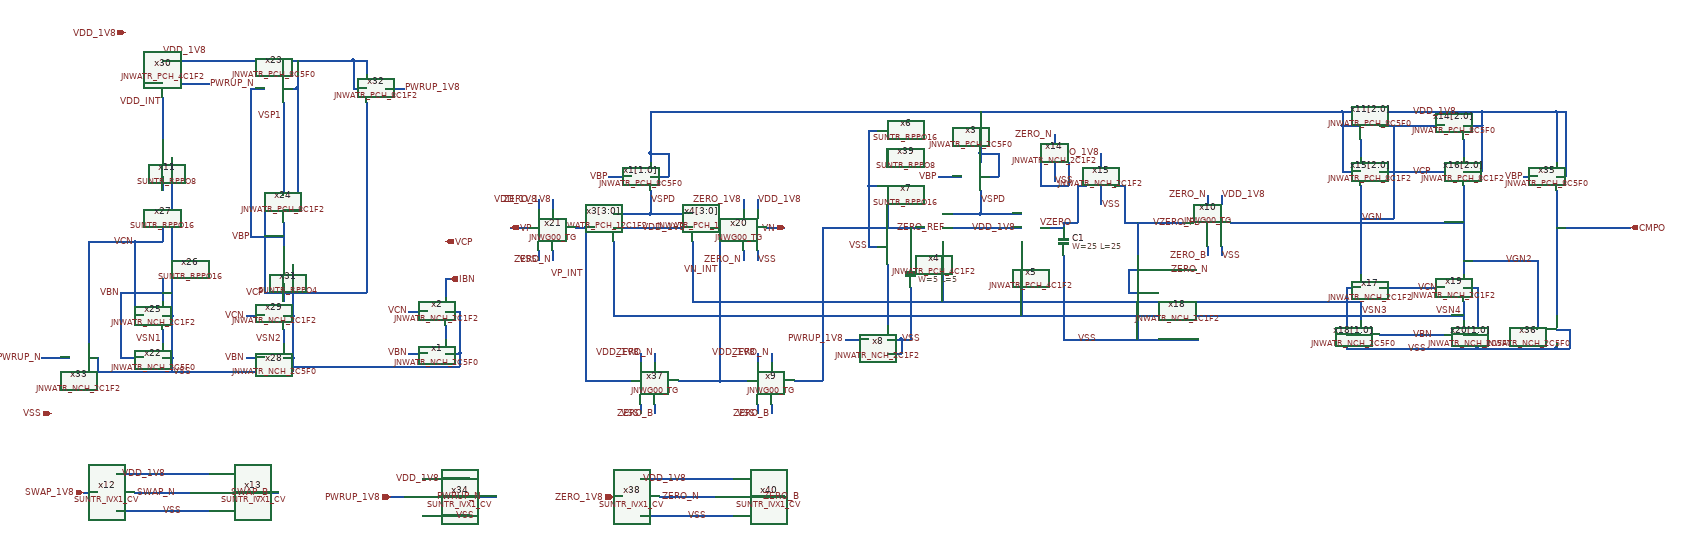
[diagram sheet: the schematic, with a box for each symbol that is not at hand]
v {xschem version=3.4.5 file_version=1.2
}
G {}
K {}
V {}
S {}
E {}
N 360 -610 460 -610 {
lab=VDD_1V8}
N 360 -530 460 -530 {
lab=VSS}
N 400 -570 420 -570 {
lab=SWAP_N}
N 290 -570 320 -570 {
lab=SWAP_1V8}
N 460 -530 560 -530 {
lab=VSS}
N 460 -610 550 -610 {
lab=VDD_1V8}
N 420 -570 520 -570 {
lab=SWAP_N}
N 600 -570 710 -570 {
lab=SWAP_B}
N 3000 -1360 3040 -1360 {
lab=VDD_1V8}
N 3000 -1390 3000 -1360 {
lab=VDD_1V8}
N 3000 -1390 3040 -1390 {
lab=VDD_1V8}
N 3040 -1390 3260 -1390 {
lab=VDD_1V8}
N 3260 -1360 3300 -1360 {
lab=VDD_1V8}
N 3300 -1390 3300 -1360 {
lab=VDD_1V8}
N 3260 -1390 3300 -1390 {
lab=VDD_1V8}
N 3260 -1330 3260 -1290 {
lab=#net1}
N 3040 -1330 3040 -1290 {
lab=#net2}
N 3000 -1260 3040 -1260 {
lab=VDD_1V8}
N 3000 -1360 3000 -1260 {
lab=VDD_1V8}
N 3260 -1260 3300 -1260 {
lab=VDD_1V8}
N 3300 -1360 3300 -1260 {
lab=VDD_1V8}
N 3040 -980 3040 -940 {
lab=VSN3}
N 3010 -1010 3040 -1010 {
lab=VSS}
N 3010 -1010 3010 -880 {
lab=VSS}
N 3010 -880 3040 -880 {
lab=VSS}
N 3010 -910 3040 -910 {
lab=VSS}
N 3260 -980 3260 -940 {
lab=VSN4}
N 3260 -1010 3290 -1010 {
lab=VSS}
N 3290 -1010 3290 -880 {
lab=VSS}
N 3260 -880 3290 -880 {
lab=VSS}
N 3260 -910 3290 -910 {
lab=VSS}
N 3040 -1230 3040 -1040 {
lab=VGN}
N 3040 -880 3260 -880 {
lab=VSS}
N 3080 -910 3120 -910 {
lab=VBN}
N 3080 -1010 3220 -1010 {
lab=VCN}
N 3080 -1260 3220 -1260 {
lab=VCP}
N 3080 -1360 3220 -1360 {
lab=VGN}
N 460 -920 460 -890 {
lab=VSN1}
N 460 -860 480 -860 {
lab=VSS}
N 480 -860 480 -830 {
lab=VSS}
N 460 -830 480 -830 {
lab=VSS}
N 480 -950 480 -860 {
lab=VSS}
N 460 -950 480 -950 {
lab=VSS}
N 460 -1030 460 -980 {
lab=VBN}
N 370 -860 420 -860 {
lab=VBN}
N 370 -1000 370 -860 {
lab=VBN}
N 370 -1000 460 -1000 {
lab=VBN}
N 400 -950 420 -950 {
lab=VCN}
N 400 -1110 400 -950 {
lab=VCN}
N 400 -1110 460 -1110 {
lab=VCN}
N 480 -1070 480 -950 {
lab=VSS}
N 480 -1180 480 -1070 {
lab=VSS}
N 460 -1140 460 -1110 {
lab=VCN}
N 420 -1450 460 -1450 {
lab=VDD_1V8}
N 420 -1480 420 -1450 {
lab=VDD_1V8}
N 420 -1480 460 -1480 {
lab=VDD_1V8}
N 460 -1520 460 -1480 {
lab=VDD_1V8}
N 500 -1450 560 -1450 {
lab=PWRUP_N}
N 720 -920 720 -890 {
lab=VSN2}
N 720 -950 740 -950 {
lab=VSS}
N 740 -950 740 -860 {
lab=VSS}
N 720 -860 740 -860 {
lab=VSS}
N 720 -830 740 -830 {
lab=VSS}
N 740 -860 740 -830 {
lab=VSS}
N 640 -950 680 -950 {
lab=VCN}
N 640 -860 680 -860 {
lab=VBN}
N 740 -1060 740 -950 {
lab=VSS}
N 720 -1020 720 -980 {
lab=VCP}
N 720 -1150 720 -1100 {
lab=VBP}
N 720 -1180 750 -1180 {
lab=VDD_1V8}
N 750 -1280 750 -1180 {
lab=VDD_1V8}
N 720 -1440 750 -1440 {
lab=VDD_1V8}
N 750 -1470 750 -1440 {
lab=VDD_1V8}
N 720 -1410 720 -1370 {
lab=VSP1}
N 680 -1180 680 -1000 {
lab=VCP}
N 680 -1000 720 -1000 {
lab=VCP}
N 650 -1120 720 -1120 {
lab=VBP}
N 650 -1280 650 -1120 {
lab=VBP}
N 650 -1440 680 -1440 {
lab=VBP}
N 460 -1500 720 -1500 {
lab=VDD_1V8}
N 720 -1500 720 -1470 {
lab=VDD_1V8}
N 900 -1260 900 -1000 {
lab=VCP}
N 720 -1000 900 -1000 {
lab=VCP}
N 870 -1440 900 -1440 {
lab=VDD_1V8}
N 870 -1500 870 -1440 {
lab=VDD_1V8}
N 870 -1500 900 -1500 {
lab=VDD_1V8}
N 900 -1500 900 -1470 {
lab=VDD_1V8}
N 720 -1500 870 -1500 {
lab=VDD_1V8}
N 940 -1440 980 -1440 {
lab=PWRUP_1V8}
N 300 -830 460 -830 {
lab=VSS}
N 300 -860 320 -860 {
lab=VSS}
N 320 -860 320 -830 {
lab=VSS}
N 300 -1110 300 -890 {
lab=VCN}
N 300 -1110 400 -1110 {
lab=VCN}
N 200 -860 260 -860 {
lab=PWRUP_N}
N 480 -830 720 -830 {
lab=VSS}
N 1020 -600 1120 -600 {
lab=VDD_1V8}
N 1020 -520 1120 -520 {
lab=VSS}
N 1060 -560 1080 -560 {
lab=PWRUP_N}
N 950 -560 980 -560 {
lab=PWRUP_1V8}
N 1080 -560 1180 -560 {
lab=PWRUP_N}
N 3120 -910 3220 -910 {
lab=VBN}
N 750 -1500 750 -1470 {
lab=VDD_1V8}
N 550 -610 560 -610 {
lab=VDD_1V8}
N 750 -1440 750 -1280 {
lab=VDD_1V8}
N 720 -1370 720 -1210 {
lab=VSP1}
N 900 -1410 900 -1260 {
lab=VCP}
N 460 -1250 460 -1220 {
lab=#net3}
N 480 -1290 480 -1180 {
lab=VSS}
N 650 -1440 650 -1280 {
lab=VBP}
N 460 -1340 460 -1330 {
lab=VDD_INT}
N 460 -1420 460 -1400 {
lab=VDD_INT}
N 3260 -1100 3260 -1040 {
lab=VGN2}
N 3260 -1230 3260 -1180 {
lab=VGN2}
N 3460 -1390 3460 -1280 {
lab=VDD_1V8}
N 3300 -1390 3460 -1390 {
lab=VDD_1V8}
N 3460 -1250 3480 -1250 {
lab=VDD_1V8}
N 3480 -1390 3480 -1250 {
lab=VDD_1V8}
N 3460 -1390 3480 -1390 {
lab=VDD_1V8}
N 3460 -890 3460 -880 {
lab=VSS}
N 3290 -880 3460 -880 {
lab=VSS}
N 3460 -920 3490 -920 {
lab=VSS}
N 3490 -920 3490 -880 {
lab=VSS}
N 3460 -880 3490 -880 {
lab=VSS}
N 3460 -980 3460 -950 {
lab=CMPO}
N 3460 -1220 3460 -980 {
lab=CMPO}
N 3460 -1140 3620 -1140 {
lab=CMPO}
N 3390 -1250 3420 -1250 {
lab=VBP}
N 3420 -1070 3420 -920 {
lab=VGN2}
N 3260 -1070 3420 -1070 {
lab=VGN2}
N 3260 -1180 3260 -1100 {
lab=VGN2}
N 1510 -1250 1550 -1250 {
lab=VDD_1V8}
N 1550 -1300 1550 -1250 {
lab=VDD_1V8}
N 1510 -1300 1550 -1300 {
lab=VDD_1V8}
N 1510 -1300 1510 -1280 {
lab=VDD_1V8}
N 1510 -1220 1510 -1170 {
lab=VSPD}
N 1430 -1170 1510 -1170 {
lab=VSPD}
N 1510 -1170 1600 -1170 {
lab=VSPD}
N 1430 -1140 1600 -1140 {
lab=VDD_1V8}
N 1550 -1390 3000 -1390 {
lab=VDD_1V8}
N 1600 -1110 1600 -980 {
lab=VSN3}
N 1600 -980 3040 -980 {
lab=VSN3}
N 1430 -1110 1430 -950 {
lab=VSN4}
N 1430 -950 3260 -950 {
lab=VSN4}
N 1420 -1250 1470 -1250 {
lab=VBP}
N 460 -1400 460 -1340 {
lab=VDD_INT}
N 1510 -1390 1510 -1300 {
lab=VDD_1V8}
N 1510 -1390 1550 -1390 {
lab=VDD_1V8}
N 3110 -1360 3110 -1160 {
lab=VGN}
N 3040 -1160 3110 -1160 {
lab=VGN}
N 990 -960 1030 -960 {
lab=VCN}
N 990 -870 1030 -870 {
lab=VBN}
N 740 -840 1070 -840 {
lab=VSS}
N 1070 -1030 1080 -1030 {
lab=IBN}
N 1070 -1030 1070 -990 {
lab=IBN}
N 1070 -930 1070 -900 {
lab=#net4}
N 1070 -960 1100 -960 {
lab=VSS}
N 1100 -960 1100 -870 {
lab=VSS}
N 1070 -870 1100 -870 {
lab=VSS}
N 1070 -840 1100 -840 {
lab=VSS}
N 1100 -870 1100 -840 {
lab=VSS}
N 1980 -1100 2000 -1100 {
lab=VSS}
N 1980 -1230 1980 -1100 {
lab=VSS}
N 2020 -1060 2020 -930 {
lab=#net5}
N 2020 -900 2050 -900 {
lab=VSS}
N 2050 -900 2050 -870 {
lab=VSS}
N 2020 -870 2050 -870 {
lab=VSS}
N 1930 -900 1980 -900 {
lab=PWRUP_1V8}
N 2020 -1190 2020 -1140 {
lab=ZERO_REF}
N 2020 -1140 2100 -1140 {
lab=ZERO_REF}
N 2400 -1080 2400 -900 {
lab=VSS}
N 2070 -1140 2070 -1070 {
lab=ZERO_REF}
N 2070 -1010 2070 -900 {
lab=VSS}
N 2050 -900 2070 -900 {
lab=VSS}
N 2350 -1140 2400 -1140 {
lab=VZERO}
N 2400 -1150 2400 -1140 {
lab=VZERO}
N 2400 -900 2500 -900 {
lab=VSS}
N 2530 -1150 2660 -1150 {
lab=VZERO_FB}
N 2500 -900 2690 -900 {
lab=VSS}
N 2560 -1150 2560 -1080 {
lab=VZERO_FB}
N 2560 -1020 2560 -900 {
lab=VSS}
N 1640 -1140 1660 -1140 {
lab=VN_INT}
N 1740 -1200 1740 -1180 {
lab=VDD_1V8}
N 1710 -1200 1710 -1180 {
lab=ZERO_1V8}
N 1710 -1090 1710 -1070 {
lab=ZERO_N}
N 1740 -1090 1740 -1070 {
lab=VSS}
N 1350 -1140 1370 -1140 {
lab=VP_INT}
N 1270 -1200 1270 -1180 {
lab=VDD_1V8}
N 1300 -1200 1300 -1180 {
lab=ZERO_1V8}
N 1300 -1090 1300 -1070 {
lab=ZERO_N}
N 1270 -1090 1270 -1070 {
lab=VSS}
N 1370 -1140 1390 -1140 {
lab=VP_INT}
N 1490 -870 1490 -850 {
lab=VDD_1V8}
N 1520 -870 1520 -850 {
lab=ZERO_N}
N 1520 -760 1520 -740 {
lab=ZERO_B}
N 1490 -760 1490 -740 {
lab=VSS}
N 1570 -810 1660 -810 {
lab=VN_INT}
N 1660 -1140 1660 -810 {
lab=VN_INT}
N 1370 -810 1460 -810 {
lab=VP_INT}
N 1370 -1140 1370 -810 {
lab=VP_INT}
N 1210 -1140 1250 -1140 {
lab=VP}
N 1760 -1140 1800 -1140 {
lab=VN}
N 1490 -600 1590 -600 {
lab=VDD_1V8}
N 1490 -520 1590 -520 {
lab=VSS}
N 1530 -560 1550 -560 {
lab=ZERO_N}
N 1550 -560 1650 -560 {
lab=ZERO_N}
N 1430 -560 1450 -560 {
lab=ZERO_1V8}
N 1460 -810 1470 -810 {
lab=VP_INT}
N 2220 -1250 2260 -1250 {
lab=VDD_1V8}
N 2260 -1300 2260 -1250 {
lab=VDD_1V8}
N 2220 -1300 2260 -1300 {
lab=VDD_1V8}
N 2220 -1300 2220 -1280 {
lab=VDD_1V8}
N 2220 -1220 2220 -1170 {
lab=VSPD}
N 2140 -1170 2220 -1170 {
lab=VSPD}
N 2220 -1170 2310 -1170 {
lab=VSPD}
N 2140 -1140 2310 -1140 {
lab=VDD_1V8}
N 2130 -1250 2180 -1250 {
lab=VBP}
N 2220 -1390 2220 -1300 {
lab=VDD_1V8}
N 1980 -1350 2000 -1350 {
lab=VSS}
N 1980 -1350 1980 -1230 {
lab=VSS}
N 2020 -1310 2020 -1270 {
lab=#net6}
N 1980 -1230 2000 -1230 {
lab=VSS}
N 2600 -1050 2630 -1050 {
lab=ZERO_N}
N 1590 -600 1680 -600 {
lab=VDD_1V8}
N 1590 -520 1690 -520 {
lab=VSS}
N 1730 -560 1800 -560 {
lab=ZERO_B}
N 2740 -1210 2740 -1190 {
lab=VDD_1V8}
N 2710 -1210 2710 -1190 {
lab=ZERO_N}
N 2710 -1100 2710 -1080 {
lab=ZERO_B}
N 2740 -1100 2740 -1080 {
lab=VSS}
N 2540 -1050 2560 -1050 {
lab=VSS}
N 2540 -1050 2540 -1000 {
lab=VSS}
N 2540 -1000 2560 -1000 {
lab=VSS}
N 2400 -1150 2430 -1150 {
lab=VZERO}
N 1680 -600 1690 -600 {
lab=VDD_1V8}
N 1740 -870 1740 -850 {
lab=VDD_1V8}
N 1770 -870 1770 -850 {
lab=ZERO_N}
N 1770 -760 1770 -740 {
lab=ZERO_B}
N 1740 -760 1740 -740 {
lab=VSS}
N 1660 -810 1720 -810 {
lab=VN_INT}
N 1880 -1140 2020 -1140 {
lab=ZERO_REF}
N 1880 -1140 1880 -810 {
lab=ZERO_REF}
N 1820 -810 1880 -810 {
lab=ZERO_REF}
N 2430 -1230 2450 -1230 {
lab=VZERO}
N 2430 -1230 2430 -1150 {
lab=VZERO}
N 2510 -1230 2530 -1230 {
lab=VZERO_FB}
N 2530 -1230 2530 -1150 {
lab=VZERO_FB}
N 2480 -1230 2480 -1190 {
lab=VSS}
N 2480 -1300 2480 -1270 {
lab=ZERO_1V8}
N 2380 -1280 2380 -1240 {
lab=VSS}
N 2410 -1280 2410 -1230 {
lab=#net7}
N 2350 -1280 2350 -1230 {
lab=#net7}
N 2350 -1230 2410 -1230 {
lab=#net7}
N 2380 -1340 2380 -1320 {
lab=ZERO_N}
N 2760 -1150 3260 -1150 {
lab=VGN2}
N 2140 -1110 2140 -980 {
lab=VSN3}
N 2310 -1110 2310 -950 {
lab=VSN4}
C {devices/ipin.sym} 290 -570 0 0 {name=p10 lab=SWAP_1V8}
C {SUN_TR_SKY130NM/SUNTR_IVX1_CV.sym} 320 -570 0 0 {name=x12 }
C {SUN_TR_SKY130NM/SUNTR_IVX1_CV.sym} 520 -570 0 0 {name=x13 }
C {devices/lab_wire.sym} 470 -610 0 0 {name=p11 sig_type=std_logic lab=VDD_1V8}
C {devices/lab_wire.sym} 490 -570 0 0 {name=p12 sig_type=std_logic lab=SWAP_N}
C {devices/lab_wire.sym} 690 -570 0 0 {name=p13 sig_type=std_logic lab=SWAP_B}
C {devices/lab_wire.sym} 460 -530 0 1 {name=p14 sig_type=std_logic lab=VSS}
C {devices/ipin.sym} 1800 -1140 2 0 {name=p25 lab=VN}
C {devices/ipin.sym} 1210 -1140 2 1 {name=p26 lab=VP}
C {JNW_ATR_SKY130NM/JNWATR_PCH_8C5F0.sym} 3080 -1360 0 1 {name=x11[2:0]}
C {JNW_ATR_SKY130NM/JNWATR_PCH_8C5F0.sym} 3220 -1360 0 0 {name=x14[2:0]}
C {JNW_ATR_SKY130NM/JNWATR_PCH_8C1F2.sym} 3080 -1260 0 1 {name=x15[2:0]}
C {JNW_ATR_SKY130NM/JNWATR_PCH_8C1F2.sym} 3220 -1260 0 0 {name=x16[2:0]}
C {JNW_ATR_SKY130NM/JNWATR_NCH_2C1F2.sym} 3080 -1010 0 1 {name=x17 }
C {JNW_ATR_SKY130NM/JNWATR_NCH_2C5F0.sym} 3080 -910 0 1 {name=x18[1:0]}
C {JNW_ATR_SKY130NM/JNWATR_NCH_2C1F2.sym} 3220 -1010 0 0 {name=x19 }
C {JNW_ATR_SKY130NM/JNWATR_NCH_2C5F0.sym} 3220 -910 0 0 {name=x20[1:0]}
C {devices/lab_wire.sym} 3140 -880 0 1 {name=p9 sig_type=std_logic lab=VSS}
C {devices/lab_wire.sym} 3150 -1390 0 1 {name=p27 sig_type=std_logic lab=VDD_1V8}
C {devices/lab_wire.sym} 3160 -1010 0 1 {name=p28 sig_type=std_logic lab=VCN}
C {devices/lab_wire.sym} 3150 -1260 0 1 {name=p29 sig_type=std_logic lab=VCP}
C {JNW_ATR_SKY130NM/JNWATR_NCH_2C5F0.sym} 420 -860 0 0 {name=x22 }
C {JNW_ATR_SKY130NM/JNWATR_PCH_8C5F0.sym} 680 -1440 0 0 {name=x23 }
C {JNW_ATR_SKY130NM/JNWATR_PCH_8C1F2.sym} 680 -1180 0 0 {name=x24 }
C {JNW_ATR_SKY130NM/JNWATR_NCH_2C1F2.sym} 420 -950 0 0 {name=x25 }
C {SUN_TR_SKY130NM/SUNTR_RPPO16.sym} 460 -1030 3 0 {name=x26 }
C {SUN_TR_SKY130NM/SUNTR_RPPO16.sym} 460 -1140 3 0 {name=x27 }
C {devices/lab_wire.sym} 460 -1520 0 1 {name=p33 sig_type=std_logic lab=VDD_1V8}
C {devices/lab_wire.sym} 480 -830 0 1 {name=p34 sig_type=std_logic lab=VSS}
C {JNW_ATR_SKY130NM/JNWATR_NCH_2C5F0.sym} 680 -860 0 0 {name=x28 }
C {JNW_ATR_SKY130NM/JNWATR_NCH_2C1F2.sym} 680 -950 0 0 {name=x29 }
C {JNW_ATR_SKY130NM/JNWATR_PCH_4C1F2.sym} 500 -1450 0 1 {name=x30 }
C {devices/lab_wire.sym} 560 -1450 0 1 {name=p35 sig_type=std_logic lab=PWRUP_N}
C {devices/lab_wire.sym} 370 -1000 0 0 {name=p36 sig_type=std_logic lab=VBN}
C {devices/lab_wire.sym} 400 -1110 0 0 {name=p37 sig_type=std_logic lab=VCN}
C {devices/lab_wire.sym} 640 -950 0 0 {name=p38 sig_type=std_logic lab=VCN}
C {devices/lab_wire.sym} 640 -860 0 0 {name=p39 sig_type=std_logic lab=VBN}
C {SUN_TR_SKY130NM/SUNTR_RPPO4.sym} 720 -1020 3 0 {name=x31 }
C {devices/lab_wire.sym} 680 -1000 0 0 {name=p40 sig_type=std_logic lab=VCP}
C {devices/lab_wire.sym} 650 -1120 0 0 {name=p41 sig_type=std_logic lab=VBP}
C {JNW_ATR_SKY130NM/JNWATR_PCH_8C1F2.sym} 940 -1440 0 1 {name=x32 }
C {devices/lab_wire.sym} 980 -1440 0 1 {name=p42 sig_type=std_logic lab=PWRUP_1V8}
C {JNW_ATR_SKY130NM/JNWATR_NCH_2C1F2.sym} 260 -860 0 0 {name=x33 }
C {devices/lab_wire.sym} 200 -860 0 0 {name=p43 sig_type=std_logic lab=PWRUP_N}
C {devices/ipin.sym} 220 -740 0 0 {name=p45 lab=VSS}
C {devices/ipin.sym} 1430 -560 0 0 {name=p46 lab=ZERO_1V8}
C {devices/ipin.sym} 950 -560 0 0 {name=p47 lab=PWRUP_1V8}
C {SUN_TR_SKY130NM/SUNTR_IVX1_CV.sym} 980 -560 0 0 {name=x34 }
C {devices/lab_wire.sym} 1060 -600 0 0 {name=p48 sig_type=std_logic lab=VDD_1V8}
C {devices/lab_wire.sym} 1150 -560 0 0 {name=p49 sig_type=std_logic lab=PWRUP_N}
C {devices/lab_wire.sym} 1090 -520 0 1 {name=p51 sig_type=std_logic lab=VSS}
C {devices/opin.sym} 3620 -1140 0 0 {name=p50 lab=CMPO
}
C {devices/ipin.sym} 380 -1560 0 0 {name=p44 lab=VDD_1V8}
C {devices/lab_wire.sym} 460 -900 0 0 {name=p53 sig_type=std_logic lab=VSN1}
C {devices/lab_wire.sym} 720 -900 0 0 {name=p54 sig_type=std_logic lab=VSN2}
C {devices/lab_wire.sym} 720 -1380 0 0 {name=p55 sig_type=std_logic lab=VSP1}
C {devices/lab_wire.sym} 460 -1410 0 0 {name=p57 sig_type=std_logic lab=VDD_INT}
C {devices/lab_wire.sym} 3040 -1160 0 1 {name=p60 sig_type=std_logic lab=VGN}
C {devices/lab_wire.sym} 3040 -960 0 1 {name=p61 sig_type=std_logic lab=VSN3}
C {devices/lab_wire.sym} 3260 -960 0 0 {name=p62 sig_type=std_logic lab=VSN4}
C {SUN_TR_SKY130NM/SUNTR_RPPO8.sym} 460 -1250 3 0 {name=x11 }
C {JNW_ATR_SKY130NM/JNWATR_PCH_8C5F0.sym} 3420 -1250 0 0 {name=x35 }
C {JNW_ATR_SKY130NM/JNWATR_NCH_2C5F0.sym} 3420 -920 0 0 {name=x36 }
C {devices/lab_wire.sym} 3350 -1070 0 1 {name=p64 sig_type=std_logic lab=VGN2}
C {devices/lab_wire.sym} 3390 -1250 0 0 {name=p63 sig_type=std_logic lab=VBP}
C {JNW_ATR_SKY130NM/JNWATR_PCH_12C1F2.sym} 1390 -1140 0 0 {name=x3[3:0]}
C {JNW_ATR_SKY130NM/JNWATR_PCH_12C1F2.sym} 1640 -1140 0 1 {name=x4[3:0]}
C {JNW_ATR_SKY130NM/JNWATR_PCH_8C5F0.sym} 1470 -1250 0 0 {name=x1[1:0]}
C {devices/lab_wire.sym} 1420 -1250 0 0 {name=p65 sig_type=std_logic lab=VBP}
C {devices/lab_wire.sym} 1510 -1200 0 1 {name=p66 sig_type=std_logic lab=VSPD}
C {devices/lab_wire.sym} 3150 -910 0 1 {name=p31 sig_type=std_logic lab=VBN}
C {JNW_ATR_SKY130NM/JNWATR_NCH_2C5F0.sym} 1030 -870 0 0 {name=x1 }
C {JNW_ATR_SKY130NM/JNWATR_NCH_2C1F2.sym} 1030 -960 0 0 {name=x2 }
C {devices/lab_wire.sym} 990 -960 0 0 {name=p1 sig_type=std_logic lab=VCN}
C {devices/lab_wire.sym} 990 -870 0 0 {name=p2 sig_type=std_logic lab=VBN}
C {devices/opin.sym} 1080 -1030 0 0 {name=p3 lab=IBN}
C {devices/opin.sym} 1070 -1110 0 0 {name=p4 lab=VCP}
C {devices/lab_wire.sym} 1490 -1140 0 1 {name=p15 sig_type=std_logic lab=VDD_1V8}
C {devices/lab_wire.sym} 2430 -900 0 1 {name=p6 sig_type=std_logic lab=VSS}
C {SUN_TR_SKY130NM/SUNTR_RPPO16.sym} 2020 -1390 1 0 {name=x6 }
C {SUN_TR_SKY130NM/SUNTR_RPPO16.sym} 2020 -1140 1 0 {name=x7 }
C {JNW_ATR_SKY130NM/JNWATR_NCH_2C1F2.sym} 1980 -900 0 0 {name=x8 }
C {devices/lab_wire.sym} 1930 -900 0 0 {name=p8 sig_type=std_logic lab=PWRUP_1V8}
C {devices/lab_wire.sym} 2050 -900 0 1 {name=p16 sig_type=std_logic lab=VSS}
C {devices/lab_wire.sym} 1980 -1100 0 0 {name=p17 sig_type=std_logic lab=VSS}
C {sky130_fd_pr/cap_mim_m3_1.sym} 2400 -1110 0 0 {name=C1 model=cap_mim_m3_1 W=25 L=25 MF=1 spiceprefix=X}
C {sky130_fd_pr/cap_mim_m3_1.sym} 2070 -1040 0 0 {name=C2 model=cap_mim_m3_1 W=5 L=5 MF=1 spiceprefix=X}
C {JNW_ATR_SKY130NM/JNWATR_NCH_2C1F2.sym} 2600 -1050 0 1 {name=x18 }
C {JNW_GR00_SKY130NM/JNWG00_TG.sym} 1650 -1140 0 0 {name=x20}
C {devices/lab_wire.sym} 1740 -1200 0 1 {name=p18 sig_type=std_logic lab=VDD_1V8}
C {devices/lab_wire.sym} 1740 -1070 0 1 {name=p19 sig_type=std_logic lab=VSS}
C {devices/lab_wire.sym} 1710 -1070 1 1 {name=p20 sig_type=std_logic lab=ZERO_N}
C {devices/lab_wire.sym} 1710 -1200 3 1 {name=p21 sig_type=std_logic lab=ZERO_1V8}
C {JNW_GR00_SKY130NM/JNWG00_TG.sym} 1360 -1140 0 1 {name=x21}
C {devices/lab_wire.sym} 1270 -1200 0 0 {name=p22 sig_type=std_logic lab=VDD_1V8}
C {devices/lab_wire.sym} 1270 -1070 0 0 {name=p23 sig_type=std_logic lab=VSS}
C {devices/lab_wire.sym} 1300 -1070 3 0 {name=p24 sig_type=std_logic lab=ZERO_N}
C {devices/lab_wire.sym} 1300 -1200 1 0 {name=p30 sig_type=std_logic lab=ZERO_1V8}
C {JNW_GR00_SKY130NM/JNWG00_TG.sym} 1580 -810 0 1 {name=x37}
C {devices/lab_wire.sym} 1490 -870 0 0 {name=p32 sig_type=std_logic lab=VDD_1V8}
C {devices/lab_wire.sym} 1490 -740 0 0 {name=p52 sig_type=std_logic lab=VSS}
C {devices/lab_wire.sym} 1520 -740 3 0 {name=p56 sig_type=std_logic lab=ZERO_B}
C {devices/lab_wire.sym} 1520 -870 1 0 {name=p58 sig_type=std_logic lab=ZERO_N}
C {devices/lab_wire.sym} 2420 -1150 0 0 {name=p59 sig_type=std_logic lab=VZERO}
C {devices/lab_wire.sym} 2590 -1150 0 1 {name=p67 sig_type=std_logic lab=VZERO_FB}
C {SUN_TR_SKY130NM/SUNTR_IVX1_CV.sym} 1450 -560 0 0 {name=x38 }
C {devices/lab_wire.sym} 1590 -600 0 0 {name=p68 sig_type=std_logic lab=VDD_1V8}
C {devices/lab_wire.sym} 1620 -560 0 0 {name=p69 sig_type=std_logic lab=ZERO_N}
C {devices/lab_wire.sym} 1590 -520 0 1 {name=p71 sig_type=std_logic lab=VSS}
C {devices/lab_wire.sym} 2040 -1140 0 1 {name=p70 sig_type=std_logic lab=ZERO_REF}
C {JNW_ATR_SKY130NM/JNWATR_PCH_4C1F2.sym} 2100 -1140 0 0 {name=x4}
C {JNW_ATR_SKY130NM/JNWATR_PCH_4C1F2.sym} 2350 -1140 0 1 {name=x5}
C {JNW_ATR_SKY130NM/JNWATR_PCH_2C5F0.sym} 2180 -1250 0 0 {name=x3}
C {devices/lab_wire.sym} 2130 -1250 0 0 {name=p5 sig_type=std_logic lab=VBP}
C {devices/lab_wire.sym} 2220 -1200 0 1 {name=p7 sig_type=std_logic lab=VSPD}
C {devices/lab_wire.sym} 2200 -1140 0 1 {name=p72 sig_type=std_logic lab=VDD_1V8}
C {SUN_TR_SKY130NM/SUNTR_RPPO8.sym} 2020 -1270 1 0 {name=x39 }
C {devices/lab_wire.sym} 2630 -1050 0 1 {name=p74 sig_type=std_logic lab=ZERO_N}
C {SUN_TR_SKY130NM/SUNTR_IVX1_CV.sym} 1650 -560 0 0 {name=x40 }
C {devices/lab_wire.sym} 1750 -560 0 1 {name=p75 sig_type=std_logic lab=ZERO_B}
C {JNW_GR00_SKY130NM/JNWG00_TG.sym} 2650 -1150 0 0 {name=x10}
C {devices/lab_wire.sym} 2740 -1210 0 1 {name=p73 sig_type=std_logic lab=VDD_1V8}
C {devices/lab_wire.sym} 2740 -1080 0 1 {name=p80 sig_type=std_logic lab=VSS}
C {devices/lab_wire.sym} 2710 -1080 1 1 {name=p81 sig_type=std_logic lab=ZERO_B}
C {devices/lab_wire.sym} 2710 -1210 3 1 {name=p82 sig_type=std_logic lab=ZERO_N}
C {devices/lab_wire.sym} 1370 -1040 0 0 {name=p76 sig_type=std_logic lab=VP_INT}
C {devices/lab_wire.sym} 1660 -1050 0 0 {name=p77 sig_type=std_logic lab=VN_INT}
C {JNW_GR00_SKY130NM/JNWG00_TG.sym} 1830 -810 0 1 {name=x9}
C {devices/lab_wire.sym} 1740 -870 0 0 {name=p78 sig_type=std_logic lab=VDD_1V8}
C {devices/lab_wire.sym} 1740 -740 0 0 {name=p79 sig_type=std_logic lab=VSS}
C {devices/lab_wire.sym} 1770 -740 3 0 {name=p87 sig_type=std_logic lab=ZERO_B}
C {devices/lab_wire.sym} 1770 -870 1 0 {name=p88 sig_type=std_logic lab=ZERO_N}
C {JNW_ATR_SKY130NM/JNWATR_NCH_2C1F2.sym} 2480 -1270 3 1 {name=x15}
C {devices/lab_wire.sym} 2480 -1190 0 1 {name=p83 sig_type=std_logic lab=VSS}
C {devices/lab_wire.sym} 2480 -1300 3 1 {name=p84 sig_type=std_logic lab=ZERO_1V8}
C {JNW_ATR_SKY130NM/JNWATR_NCH_2C1F2.sym} 2380 -1320 3 1 {name=x14}
C {devices/lab_wire.sym} 2380 -1240 0 1 {name=p85 sig_type=std_logic lab=VSS}
C {devices/lab_wire.sym} 2380 -1340 3 1 {name=p86 sig_type=std_logic lab=ZERO_N}
